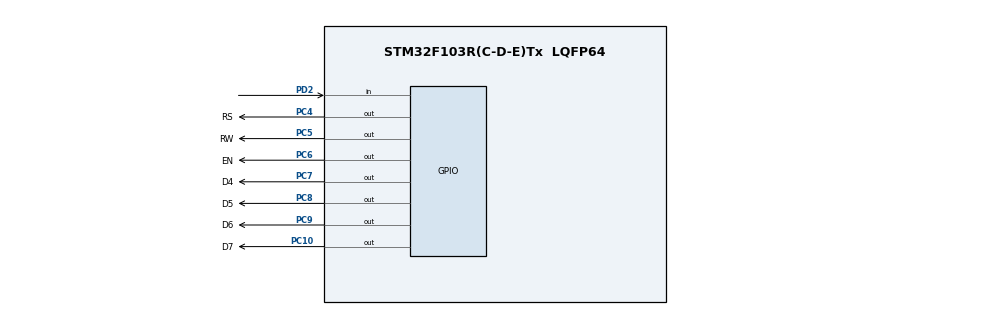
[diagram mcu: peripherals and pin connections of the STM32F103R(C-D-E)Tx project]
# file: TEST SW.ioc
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Mcu.Family=STM32F1
Mcu.Name=STM32F103R(C-D-E)Tx
Mcu.Package=LQFP64
NVIC.PriorityGroup=NVIC_PRIORITYGROUP_4
PA13.Mode=JTAG_4_pins
PA13.Signal=SYS_JTMS-SWDIO
PA14.Mode=JTAG_4_pins
PA14.Signal=SYS_JTCK-SWCLK
PA15.Mode=JTAG_4_pins
PA15.Signal=SYS_JTDI
PB3.Mode=JTAG_4_pins
PB3.Signal=SYS_JTDO-TRACESWO
PC10.GPIO_Label=D7
PC10.Signal=GPIO_Output
PC4.GPIO_Label=RS
PC4.Signal=GPIO_Output
PC5.GPIO_Label=RW
PC5.Signal=GPIO_Output
PC6.GPIO_Label=EN
PC6.Signal=GPIO_Output
PC7.GPIO_Label=D4
PC7.Signal=GPIO_Output
PC8.GPIO_Label=D5
PC8.Signal=GPIO_Output
PC9.GPIO_Label=D6
PC9.Signal=GPIO_Output
PD2.Signal=GPIO_Input
ProjectManager.HeapSize=0x200
ProjectManager.StackSize=0x400
ProjectManager.TargetToolchain=MDK-ARM V5
RCC.APB1Freq_Value=8000000
RCC.APB2Freq_Value=8000000
board=TEST SW

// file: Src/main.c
/**
  ******************************************************************************
  * File Name          : main.c
  * Description        : Main program body
  ******************************************************************************
  ** This notice applies to any and all portions of this file
  * that are not between comment pairs USER CODE BEGIN and
  * USER CODE END. Other portions of this file, whether
  * inserted by the user or by software development tools
  * are owned by their respective copyright owners.
  *
  * COPYRIGHT(c) 2017 STMicroelectronics
  *
  * Redistribution and use in source and binary forms, with or without modification,
  * are permitted provided that the following conditions are met:
  *   1. Redistributions of source code must retain the above copyright notice,
  *      this list of conditions and the following disclaimer.
  *   2. Redistributions in binary form must reproduce the above copyright notice,
  *      this list of conditions and the following disclaimer in the documentation
  *      and/or other materials provided with the distribution.
  *   3. Neither the name of STMicroelectronics nor the names of its contributors
  *      may be used to endorse or promote products derived from this software
  *      without specific prior written permission.
  *
  * THIS SOFTWARE IS PROVIDED BY THE COPYRIGHT HOLDERS AND CONTRIBUTORS "AS IS"
  * AND ANY EXPRESS OR IMPLIED WARRANTIES, INCLUDING, BUT NOT LIMITED TO, THE
  * IMPLIED WARRANTIES OF MERCHANTABILITY AND FITNESS FOR A PARTICULAR PURPOSE ARE
  * DISCLAIMED. IN NO EVENT SHALL THE COPYRIGHT HOLDER OR CONTRIBUTORS BE LIABLE
  * FOR ANY DIRECT, INDIRECT, INCIDENTAL, SPECIAL, EXEMPLARY, OR CONSEQUENTIAL
  * DAMAGES (INCLUDING, BUT NOT LIMITED TO, PROCUREMENT OF SUBSTITUTE GOODS OR
  * SERVICES; LOSS OF USE, DATA, OR PROFITS; OR BUSINESS INTERRUPTION) HOWEVER
  * CAUSED AND ON ANY THEORY OF LIABILITY, WHETHER IN CONTRACT, STRICT LIABILITY,
  * OR TORT (INCLUDING NEGLIGENCE OR OTHERWISE) ARISING IN ANY WAY OUT OF THE USE
  * OF THIS SOFTWARE, EVEN IF ADVISED OF THE POSSIBILITY OF SUCH DAMAGE.
  *
  ******************************************************************************
  */
#include "main.h"
#include "stm32f1xx_hal.h"
#include "lcd1602.h"
int i=0;

/* USER CODE BEGIN PV */
/* Private variables ---------------------------------------------------------*/

/* USER CODE END PV */

void SystemClock_Config(void);
static void MX_GPIO_Init(void);

/* USER CODE BEGIN PFP */
/* Private function prototypes -----------------------------------------------*/

/* USER CODE END PFP */

int main(void)
{

  /* MCU Configuration----------------------------------------------------------*/

  /* Reset of all peripherals, Initializes the Flash interface and the Systick. */
  HAL_Init();

  /* Configure the system clock */
  SystemClock_Config();

  /* Initialize all configured peripherals */
  MX_GPIO_Init();
	LCD_Init();
  LCD_Gotoxy(0,0);
	LCD_Puts("Code Tesla Thinh");
	HAL_Delay(2000);
	LCD_Clear();

  while (1)
  {

  if(HAL_GPIO_ReadPin(GPIOC,GPIO_PIN_3)==0)
		{
			HAL_Delay(50);
			while(HAL_GPIO_ReadPin(GPIOC,GPIO_PIN_3)==0)
			{
			}
			i++;
		}
	LCD_Gotoxy(0,0);
  LCD_Puts("mualinhkien.vn");
	LCD_Gotoxy(0,1);
	LCD_Puts("Test SW:");
	LCD_Gotoxy(9,1);
	LCD_PutChar(i+48);

	if(HAL_GPIO_ReadPin(GPIOC,GPIO_PIN_1)==0)
		{
			HAL_Delay(50);
			while(HAL_GPIO_ReadPin(GPIOC,GPIO_PIN_1)==0)
			{
			}
			i--;
		}

  }
  /* USER CODE END 3 */

}

/** System Clock Configuration
*/
void SystemClock_Config(void)
{

  RCC_OscInitTypeDef RCC_OscInitStruct;
  RCC_ClkInitTypeDef RCC_ClkInitStruct;

    /**Initializes the CPU, AHB and APB busses clocks
    */
  RCC_OscInitStruct.OscillatorType = RCC_OSCILLATORTYPE_HSI;
  RCC_OscInitStruct.HSIState = RCC_HSI_ON;
  RCC_OscInitStruct.HSICalibrationValue = 16;
  RCC_OscInitStruct.PLL.PLLState = RCC_PLL_NONE;
  if (HAL_RCC_OscConfig(&RCC_OscInitStruct) != HAL_OK)
  {
    _Error_Handler(__FILE__, __LINE__);
  }

    /**Initializes the CPU, AHB and APB busses clocks
    */
  RCC_ClkInitStruct.ClockType = RCC_CLOCKTYPE_HCLK|RCC_CLOCKTYPE_SYSCLK
                              |RCC_CLOCKTYPE_PCLK1|RCC_CLOCKTYPE_PCLK2;
  RCC_ClkInitStruct.SYSCLKSource = RCC_SYSCLKSOURCE_HSI;
  RCC_ClkInitStruct.AHBCLKDivider = RCC_SYSCLK_DIV1;
  RCC_ClkInitStruct.APB1CLKDivider = RCC_HCLK_DIV1;
  RCC_ClkInitStruct.APB2CLKDivider = RCC_HCLK_DIV1;

  if (HAL_RCC_ClockConfig(&RCC_ClkInitStruct, FLASH_LATENCY_0) != HAL_OK)
  {
    _Error_Handler(__FILE__, __LINE__);
  }

    /**Configure the Systick interrupt time
    */
  HAL_SYSTICK_Config(HAL_RCC_GetHCLKFreq()/1000);

    /**Configure the Systick
    */
  HAL_SYSTICK_CLKSourceConfig(SYSTICK_CLKSOURCE_HCLK);

  /* SysTick_IRQn interrupt configuration */
  HAL_NVIC_SetPriority(SysTick_IRQn, 0, 0);
}

/** Configure pins as
        * Analog
        * Input
        * Output
        * EVENT_OUT
        * EXTI
*/
static void MX_GPIO_Init(void)
{

  GPIO_InitTypeDef GPIO_InitStruct;

  /* GPIO Ports Clock Enable */
  __HAL_RCC_GPIOC_CLK_ENABLE();
  __HAL_RCC_GPIOA_CLK_ENABLE();
  __HAL_RCC_GPIOD_CLK_ENABLE();
  __HAL_RCC_GPIOB_CLK_ENABLE();

  /*Configure GPIO pin Output Level */
  HAL_GPIO_WritePin(GPIOC, RS_Pin|RW_Pin|EN_Pin|D4_Pin
                          |D5_Pin|D6_Pin|D7_Pin|GPIO_PIN_11, GPIO_PIN_RESET);

  /*Configure GPIO pins : RS_Pin RW_Pin EN_Pin D4_Pin
                           D5_Pin D6_Pin D7_Pin */
  GPIO_InitStruct.Pin = RS_Pin|RW_Pin|EN_Pin|D4_Pin
                          |D5_Pin|D6_Pin|D7_Pin|GPIO_PIN_11;
  GPIO_InitStruct.Mode = GPIO_MODE_OUTPUT_PP;
  GPIO_InitStruct.Speed = GPIO_SPEED_FREQ_LOW;
  HAL_GPIO_Init(GPIOC, &GPIO_InitStruct);

  /*Configure GPIO pin : PC3 */
  GPIO_InitStruct.Pin = GPIO_PIN_3;
  GPIO_InitStruct.Mode = GPIO_MODE_INPUT;
  GPIO_InitStruct.Pull = GPIO_NOPULL;
  HAL_GPIO_Init(GPIOC, &GPIO_InitStruct);

	/*Configure GPIO pin : PC1 */
  GPIO_InitStruct.Pin = GPIO_PIN_1;
  GPIO_InitStruct.Mode = GPIO_MODE_INPUT;
  GPIO_InitStruct.Pull = GPIO_NOPULL;
  HAL_GPIO_Init(GPIOC, &GPIO_InitStruct);
}

void _Error_Handler(char * file, int line)
{
  while(1)
  {
  }
}

/************************ (C) COPYRIGHT STMicroelectronics *****END OF FILE****/
